VERSION 5.7 ;
  NOWIREEXTENSIONATPIN ON ;
  DIVIDERCHAR "/" ;
  BUSBITCHARS "[]" ;
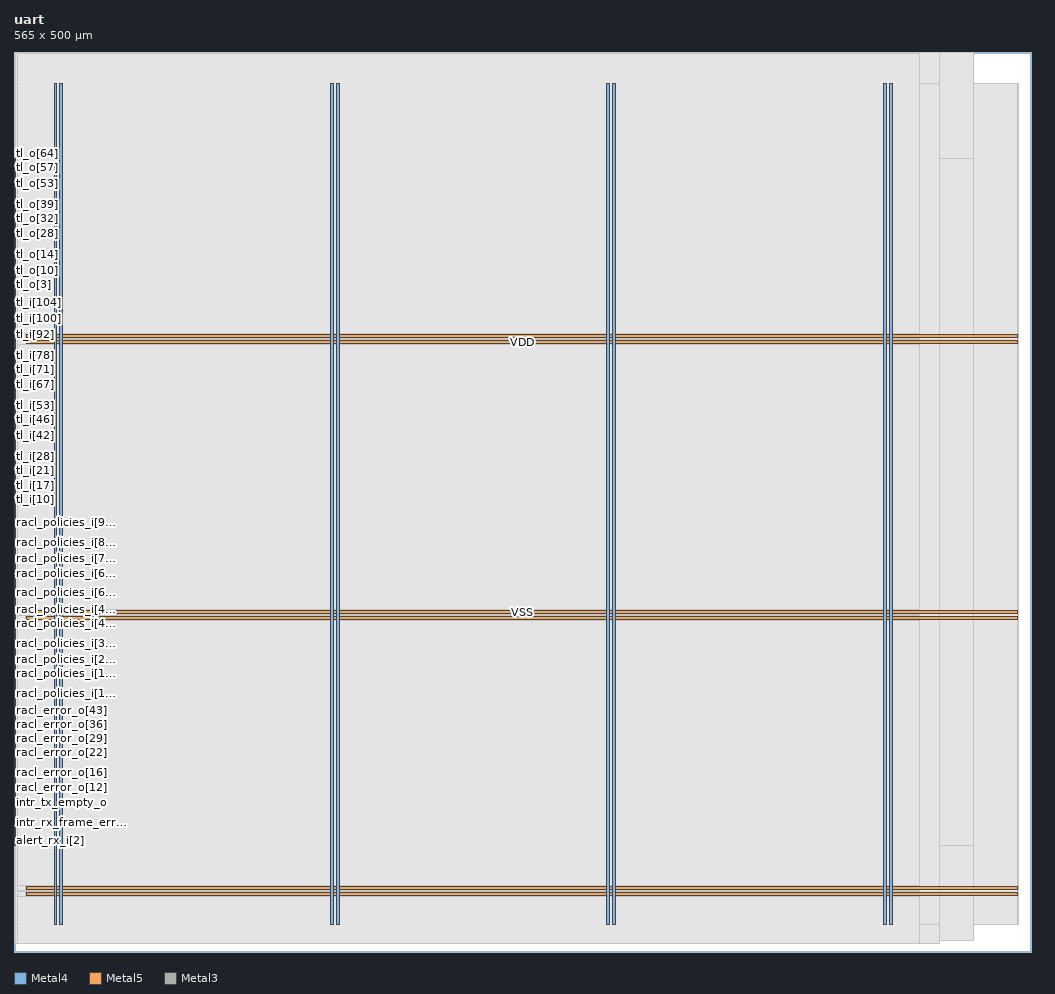
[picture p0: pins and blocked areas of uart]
MACRO uart
  CLASS BLOCK ;
  FOREIGN uart ;
  ORIGIN 0.000 0.000 ;
  SIZE 565.000 BY 500.000 ;
  PIN VDD
    DIRECTION INOUT ;
    USE POWER ;
    PORT
      LAYER Metal4 ;
        RECT 22.240 15.380 23.840 482.460 ;
    END
    PORT
      LAYER Metal4 ;
        RECT 175.840 15.380 177.440 482.460 ;
    END
    PORT
      LAYER Metal4 ;
        RECT 329.440 15.380 331.040 482.460 ;
    END
    PORT
      LAYER Metal4 ;
        RECT 483.040 15.380 484.640 482.460 ;
    END
    PORT
      LAYER Metal5 ;
        RECT 6.720 31.530 557.760 33.130 ;
    END
    PORT
      LAYER Metal5 ;
        RECT 6.720 184.710 557.760 186.310 ;
    END
    PORT
      LAYER Metal5 ;
        RECT 6.720 337.890 557.760 339.490 ;
    END
  END VDD
  PIN VSS
    DIRECTION INOUT ;
    USE GROUND ;
    PORT
      LAYER Metal4 ;
        RECT 25.540 15.380 27.140 482.460 ;
    END
    PORT
      LAYER Metal4 ;
        RECT 179.140 15.380 180.740 482.460 ;
    END
    PORT
      LAYER Metal4 ;
        RECT 332.740 15.380 334.340 482.460 ;
    END
    PORT
      LAYER Metal4 ;
        RECT 486.340 15.380 487.940 482.460 ;
    END
    PORT
      LAYER Metal5 ;
        RECT 6.720 34.830 557.760 36.430 ;
    END
    PORT
      LAYER Metal5 ;
        RECT 6.720 188.010 557.760 189.610 ;
    END
    PORT
      LAYER Metal5 ;
        RECT 6.720 341.190 557.760 342.790 ;
    END
  END VSS
  PIN alert_rx_i[0]
    DIRECTION INPUT ;
    USE SIGNAL ;
    ANTENNAGATEAREA 0.396000 ;
    PORT
      LAYER Metal3 ;
        RECT 0.000 59.360 0.560 59.920 ;
    END
  END alert_rx_i[0]
  PIN alert_rx_i[1]
    DIRECTION INPUT ;
    USE SIGNAL ;
    ANTENNAGATEAREA 0.396000 ;
    ANTENNADIFFAREA 0.410400 ;
    PORT
      LAYER Metal3 ;
        RECT 0.000 60.480 0.560 61.040 ;
    END
  END alert_rx_i[1]
  PIN alert_rx_i[2]
    DIRECTION INPUT ;
    USE SIGNAL ;
    ANTENNAGATEAREA 0.396000 ;
    ANTENNADIFFAREA 0.410400 ;
    PORT
      LAYER Metal3 ;
        RECT 0.000 61.600 0.560 62.160 ;
    END
  END alert_rx_i[2]
  PIN alert_rx_i[3]
    DIRECTION INPUT ;
    USE SIGNAL ;
    ANTENNAGATEAREA 0.396000 ;
    ANTENNADIFFAREA 0.410400 ;
    PORT
      LAYER Metal3 ;
        RECT 0.000 62.720 0.560 63.280 ;
    END
  END alert_rx_i[3]
  PIN alert_tx_o[0]
    DIRECTION OUTPUT ;
    USE SIGNAL ;
    ANTENNADIFFAREA 0.897600 ;
    PORT
      LAYER Metal3 ;
        RECT 0.000 63.840 0.560 64.400 ;
    END
  END alert_tx_o[0]
  PIN alert_tx_o[1]
    DIRECTION OUTPUT ;
    USE SIGNAL ;
    ANTENNADIFFAREA 0.897600 ;
    PORT
      LAYER Metal3 ;
        RECT 0.000 64.960 0.560 65.520 ;
    END
  END alert_tx_o[1]
  PIN cio_rx_i
    DIRECTION INPUT ;
    USE SIGNAL ;
    ANTENNAGATEAREA 0.396000 ;
    PORT
      LAYER Metal3 ;
        RECT 0.000 66.080 0.560 66.640 ;
    END
  END cio_rx_i
  PIN cio_tx_en_o
    DIRECTION OUTPUT ;
    USE SIGNAL ;
    ANTENNADIFFAREA 0.536800 ;
    PORT
      LAYER Metal3 ;
        RECT 0.000 67.200 0.560 67.760 ;
    END
  END cio_tx_en_o
  PIN cio_tx_o
    DIRECTION OUTPUT ;
    USE SIGNAL ;
    ANTENNADIFFAREA 0.897600 ;
    PORT
      LAYER Metal3 ;
        RECT 0.000 68.320 0.560 68.880 ;
    END
  END cio_tx_o
  PIN clk_i
    DIRECTION INPUT ;
    USE SIGNAL ;
    ANTENNAGATEAREA 4.738000 ;
    PORT
      LAYER Metal3 ;
        RECT 0.000 69.440 0.560 70.000 ;
    END
  END clk_i
  PIN intr_rx_break_err_o
    DIRECTION OUTPUT ;
    USE SIGNAL ;
    ANTENNADIFFAREA 0.897600 ;
    PORT
      LAYER Metal3 ;
        RECT 0.000 70.560 0.560 71.120 ;
    END
  END intr_rx_break_err_o
  PIN intr_rx_frame_err_o
    DIRECTION OUTPUT ;
    USE SIGNAL ;
    ANTENNADIFFAREA 0.897600 ;
    PORT
      LAYER Metal3 ;
        RECT 0.000 71.680 0.560 72.240 ;
    END
  END intr_rx_frame_err_o
  PIN intr_rx_overflow_o
    DIRECTION OUTPUT ;
    USE SIGNAL ;
    ANTENNADIFFAREA 0.897600 ;
    PORT
      LAYER Metal3 ;
        RECT 0.000 72.800 0.560 73.360 ;
    END
  END intr_rx_overflow_o
  PIN intr_rx_parity_err_o
    DIRECTION OUTPUT ;
    USE SIGNAL ;
    ANTENNADIFFAREA 0.897600 ;
    PORT
      LAYER Metal3 ;
        RECT 0.000 73.920 0.560 74.480 ;
    END
  END intr_rx_parity_err_o
  PIN intr_rx_timeout_o
    DIRECTION OUTPUT ;
    USE SIGNAL ;
    ANTENNADIFFAREA 0.897600 ;
    PORT
      LAYER Metal3 ;
        RECT 0.000 75.040 0.560 75.600 ;
    END
  END intr_rx_timeout_o
  PIN intr_rx_watermark_o
    DIRECTION OUTPUT ;
    USE SIGNAL ;
    ANTENNADIFFAREA 0.897600 ;
    PORT
      LAYER Metal3 ;
        RECT 0.000 76.160 0.560 76.720 ;
    END
  END intr_rx_watermark_o
  PIN intr_tx_done_o
    DIRECTION OUTPUT ;
    USE SIGNAL ;
    ANTENNADIFFAREA 0.897600 ;
    PORT
      LAYER Metal3 ;
        RECT 0.000 77.280 0.560 77.840 ;
    END
  END intr_tx_done_o
  PIN intr_tx_empty_o
    DIRECTION OUTPUT ;
    USE SIGNAL ;
    ANTENNADIFFAREA 0.897600 ;
    PORT
      LAYER Metal3 ;
        RECT 0.000 78.400 0.560 78.960 ;
    END
  END intr_tx_empty_o
  PIN intr_tx_watermark_o
    DIRECTION OUTPUT ;
    USE SIGNAL ;
    ANTENNADIFFAREA 0.897600 ;
    PORT
      LAYER Metal3 ;
        RECT 0.000 79.520 0.560 80.080 ;
    END
  END intr_tx_watermark_o
  PIN lsio_trigger_o
    DIRECTION OUTPUT ;
    USE SIGNAL ;
    ANTENNADIFFAREA 0.897600 ;
    PORT
      LAYER Metal3 ;
        RECT 0.000 80.640 0.560 81.200 ;
    END
  END lsio_trigger_o
  PIN racl_error_o[0]
    DIRECTION OUTPUT ;
    USE SIGNAL ;
    ANTENNADIFFAREA 0.360800 ;
    PORT
      LAYER Metal3 ;
        RECT 0.000 81.760 0.560 82.320 ;
    END
  END racl_error_o[0]
  PIN racl_error_o[10]
    DIRECTION OUTPUT ;
    USE SIGNAL ;
    ANTENNADIFFAREA 0.360800 ;
    PORT
      LAYER Metal3 ;
        RECT 0.000 92.960 0.560 93.520 ;
    END
  END racl_error_o[10]
  PIN racl_error_o[11]
    DIRECTION OUTPUT ;
    USE SIGNAL ;
    ANTENNADIFFAREA 0.360800 ;
    PORT
      LAYER Metal3 ;
        RECT 0.000 94.080 0.560 94.640 ;
    END
  END racl_error_o[11]
  PIN racl_error_o[12]
    DIRECTION OUTPUT ;
    USE SIGNAL ;
    ANTENNADIFFAREA 0.360800 ;
    PORT
      LAYER Metal3 ;
        RECT 0.000 95.200 0.560 95.760 ;
    END
  END racl_error_o[12]
  PIN racl_error_o[13]
    DIRECTION OUTPUT ;
    USE SIGNAL ;
    ANTENNADIFFAREA 0.360800 ;
    PORT
      LAYER Metal3 ;
        RECT 0.000 96.320 0.560 96.880 ;
    END
  END racl_error_o[13]
  PIN racl_error_o[14]
    DIRECTION OUTPUT ;
    USE SIGNAL ;
    ANTENNADIFFAREA 0.360800 ;
    PORT
      LAYER Metal3 ;
        RECT 0.000 97.440 0.560 98.000 ;
    END
  END racl_error_o[14]
  PIN racl_error_o[15]
    DIRECTION OUTPUT ;
    USE SIGNAL ;
    ANTENNADIFFAREA 0.360800 ;
    PORT
      LAYER Metal3 ;
        RECT 0.000 98.560 0.560 99.120 ;
    END
  END racl_error_o[15]
  PIN racl_error_o[16]
    DIRECTION OUTPUT ;
    USE SIGNAL ;
    ANTENNADIFFAREA 0.360800 ;
    PORT
      LAYER Metal3 ;
        RECT 0.000 99.680 0.560 100.240 ;
    END
  END racl_error_o[16]
  PIN racl_error_o[17]
    DIRECTION OUTPUT ;
    USE SIGNAL ;
    ANTENNADIFFAREA 0.360800 ;
    PORT
      LAYER Metal3 ;
        RECT 0.000 100.800 0.560 101.360 ;
    END
  END racl_error_o[17]
  PIN racl_error_o[18]
    DIRECTION OUTPUT ;
    USE SIGNAL ;
    ANTENNADIFFAREA 0.360800 ;
    PORT
      LAYER Metal3 ;
        RECT 0.000 101.920 0.560 102.480 ;
    END
  END racl_error_o[18]
  PIN racl_error_o[19]
    DIRECTION OUTPUT ;
    USE SIGNAL ;
    ANTENNADIFFAREA 0.360800 ;
    PORT
      LAYER Metal3 ;
        RECT 0.000 103.040 0.560 103.600 ;
    END
  END racl_error_o[19]
  PIN racl_error_o[1]
    DIRECTION OUTPUT ;
    USE SIGNAL ;
    ANTENNADIFFAREA 0.360800 ;
    PORT
      LAYER Metal3 ;
        RECT 0.000 82.880 0.560 83.440 ;
    END
  END racl_error_o[1]
  PIN racl_error_o[20]
    DIRECTION OUTPUT ;
    USE SIGNAL ;
    ANTENNADIFFAREA 0.360800 ;
    PORT
      LAYER Metal3 ;
        RECT 0.000 104.160 0.560 104.720 ;
    END
  END racl_error_o[20]
  PIN racl_error_o[21]
    DIRECTION OUTPUT ;
    USE SIGNAL ;
    ANTENNADIFFAREA 0.360800 ;
    PORT
      LAYER Metal3 ;
        RECT 0.000 105.280 0.560 105.840 ;
    END
  END racl_error_o[21]
  PIN racl_error_o[22]
    DIRECTION OUTPUT ;
    USE SIGNAL ;
    ANTENNADIFFAREA 0.360800 ;
    PORT
      LAYER Metal3 ;
        RECT 0.000 106.400 0.560 106.960 ;
    END
  END racl_error_o[22]
  PIN racl_error_o[23]
    DIRECTION OUTPUT ;
    USE SIGNAL ;
    ANTENNADIFFAREA 0.360800 ;
    PORT
      LAYER Metal3 ;
        RECT 0.000 107.520 0.560 108.080 ;
    END
  END racl_error_o[23]
  PIN racl_error_o[24]
    DIRECTION OUTPUT ;
    USE SIGNAL ;
    ANTENNADIFFAREA 0.360800 ;
    PORT
      LAYER Metal3 ;
        RECT 0.000 108.640 0.560 109.200 ;
    END
  END racl_error_o[24]
  PIN racl_error_o[25]
    DIRECTION OUTPUT ;
    USE SIGNAL ;
    ANTENNADIFFAREA 0.360800 ;
    PORT
      LAYER Metal3 ;
        RECT 0.000 109.760 0.560 110.320 ;
    END
  END racl_error_o[25]
  PIN racl_error_o[26]
    DIRECTION OUTPUT ;
    USE SIGNAL ;
    ANTENNADIFFAREA 0.360800 ;
    PORT
      LAYER Metal3 ;
        RECT 0.000 110.880 0.560 111.440 ;
    END
  END racl_error_o[26]
  PIN racl_error_o[27]
    DIRECTION OUTPUT ;
    USE SIGNAL ;
    ANTENNADIFFAREA 0.360800 ;
    PORT
      LAYER Metal3 ;
        RECT 0.000 112.000 0.560 112.560 ;
    END
  END racl_error_o[27]
  PIN racl_error_o[28]
    DIRECTION OUTPUT ;
    USE SIGNAL ;
    ANTENNADIFFAREA 0.360800 ;
    PORT
      LAYER Metal3 ;
        RECT 0.000 113.120 0.560 113.680 ;
    END
  END racl_error_o[28]
  PIN racl_error_o[29]
    DIRECTION OUTPUT ;
    USE SIGNAL ;
    ANTENNADIFFAREA 0.360800 ;
    PORT
      LAYER Metal3 ;
        RECT 0.000 114.240 0.560 114.800 ;
    END
  END racl_error_o[29]
  PIN racl_error_o[2]
    DIRECTION OUTPUT ;
    USE SIGNAL ;
    ANTENNADIFFAREA 0.897600 ;
    PORT
      LAYER Metal3 ;
        RECT 0.000 84.000 0.560 84.560 ;
    END
  END racl_error_o[2]
  PIN racl_error_o[30]
    DIRECTION OUTPUT ;
    USE SIGNAL ;
    ANTENNADIFFAREA 0.360800 ;
    PORT
      LAYER Metal3 ;
        RECT 0.000 115.360 0.560 115.920 ;
    END
  END racl_error_o[30]
  PIN racl_error_o[31]
    DIRECTION OUTPUT ;
    USE SIGNAL ;
    ANTENNADIFFAREA 0.360800 ;
    PORT
      LAYER Metal3 ;
        RECT 0.000 116.480 0.560 117.040 ;
    END
  END racl_error_o[31]
  PIN racl_error_o[32]
    DIRECTION OUTPUT ;
    USE SIGNAL ;
    ANTENNADIFFAREA 0.360800 ;
    PORT
      LAYER Metal3 ;
        RECT 0.000 117.600 0.560 118.160 ;
    END
  END racl_error_o[32]
  PIN racl_error_o[33]
    DIRECTION OUTPUT ;
    USE SIGNAL ;
    ANTENNADIFFAREA 0.360800 ;
    PORT
      LAYER Metal3 ;
        RECT 0.000 118.720 0.560 119.280 ;
    END
  END racl_error_o[33]
  PIN racl_error_o[34]
    DIRECTION OUTPUT ;
    USE SIGNAL ;
    ANTENNADIFFAREA 0.360800 ;
    PORT
      LAYER Metal3 ;
        RECT 0.000 119.840 0.560 120.400 ;
    END
  END racl_error_o[34]
  PIN racl_error_o[35]
    DIRECTION OUTPUT ;
    USE SIGNAL ;
    ANTENNADIFFAREA 0.360800 ;
    PORT
      LAYER Metal3 ;
        RECT 0.000 120.960 0.560 121.520 ;
    END
  END racl_error_o[35]
  PIN racl_error_o[36]
    DIRECTION OUTPUT ;
    USE SIGNAL ;
    ANTENNADIFFAREA 0.360800 ;
    PORT
      LAYER Metal3 ;
        RECT 0.000 122.080 0.560 122.640 ;
    END
  END racl_error_o[36]
  PIN racl_error_o[37]
    DIRECTION OUTPUT ;
    USE SIGNAL ;
    ANTENNADIFFAREA 0.360800 ;
    PORT
      LAYER Metal3 ;
        RECT 0.000 123.200 0.560 123.760 ;
    END
  END racl_error_o[37]
  PIN racl_error_o[38]
    DIRECTION OUTPUT ;
    USE SIGNAL ;
    ANTENNADIFFAREA 0.360800 ;
    PORT
      LAYER Metal3 ;
        RECT 0.000 124.320 0.560 124.880 ;
    END
  END racl_error_o[38]
  PIN racl_error_o[39]
    DIRECTION OUTPUT ;
    USE SIGNAL ;
    ANTENNADIFFAREA 0.360800 ;
    PORT
      LAYER Metal3 ;
        RECT 0.000 125.440 0.560 126.000 ;
    END
  END racl_error_o[39]
  PIN racl_error_o[3]
    DIRECTION OUTPUT ;
    USE SIGNAL ;
    ANTENNADIFFAREA 0.897600 ;
    PORT
      LAYER Metal3 ;
        RECT 0.000 85.120 0.560 85.680 ;
    END
  END racl_error_o[3]
  PIN racl_error_o[40]
    DIRECTION OUTPUT ;
    USE SIGNAL ;
    ANTENNADIFFAREA 0.360800 ;
    PORT
      LAYER Metal3 ;
        RECT 0.000 126.560 0.560 127.120 ;
    END
  END racl_error_o[40]
  PIN racl_error_o[41]
    DIRECTION OUTPUT ;
    USE SIGNAL ;
    ANTENNADIFFAREA 0.360800 ;
    PORT
      LAYER Metal3 ;
        RECT 0.000 127.680 0.560 128.240 ;
    END
  END racl_error_o[41]
  PIN racl_error_o[42]
    DIRECTION OUTPUT ;
    USE SIGNAL ;
    ANTENNADIFFAREA 0.360800 ;
    PORT
      LAYER Metal3 ;
        RECT 0.000 128.800 0.560 129.360 ;
    END
  END racl_error_o[42]
  PIN racl_error_o[43]
    DIRECTION OUTPUT ;
    USE SIGNAL ;
    ANTENNADIFFAREA 0.360800 ;
    PORT
      LAYER Metal3 ;
        RECT 0.000 129.920 0.560 130.480 ;
    END
  END racl_error_o[43]
  PIN racl_error_o[4]
    DIRECTION OUTPUT ;
    USE SIGNAL ;
    ANTENNADIFFAREA 0.897600 ;
    PORT
      LAYER Metal3 ;
        RECT 0.000 86.240 0.560 86.800 ;
    END
  END racl_error_o[4]
  PIN racl_error_o[5]
    DIRECTION OUTPUT ;
    USE SIGNAL ;
    ANTENNADIFFAREA 0.897600 ;
    PORT
      LAYER Metal3 ;
        RECT 0.000 87.360 0.560 87.920 ;
    END
  END racl_error_o[5]
  PIN racl_error_o[6]
    DIRECTION OUTPUT ;
    USE SIGNAL ;
    ANTENNADIFFAREA 0.360800 ;
    PORT
      LAYER Metal3 ;
        RECT 0.000 88.480 0.560 89.040 ;
    END
  END racl_error_o[6]
  PIN racl_error_o[7]
    DIRECTION OUTPUT ;
    USE SIGNAL ;
    ANTENNADIFFAREA 0.360800 ;
    PORT
      LAYER Metal3 ;
        RECT 0.000 89.600 0.560 90.160 ;
    END
  END racl_error_o[7]
  PIN racl_error_o[8]
    DIRECTION OUTPUT ;
    USE SIGNAL ;
    ANTENNADIFFAREA 0.360800 ;
    PORT
      LAYER Metal3 ;
        RECT 0.000 90.720 0.560 91.280 ;
    END
  END racl_error_o[8]
  PIN racl_error_o[9]
    DIRECTION OUTPUT ;
    USE SIGNAL ;
    ANTENNADIFFAREA 0.360800 ;
    PORT
      LAYER Metal3 ;
        RECT 0.000 91.840 0.560 92.400 ;
    END
  END racl_error_o[9]
  PIN racl_policies_i[0]
    DIRECTION INPUT ;
    USE SIGNAL ;
    PORT
      LAYER Metal3 ;
        RECT 0.000 131.040 0.560 131.600 ;
    END
  END racl_policies_i[0]
  PIN racl_policies_i[10]
    DIRECTION INPUT ;
    USE SIGNAL ;
    PORT
      LAYER Metal3 ;
        RECT 0.000 142.240 0.560 142.800 ;
    END
  END racl_policies_i[10]
  PIN racl_policies_i[11]
    DIRECTION INPUT ;
    USE SIGNAL ;
    PORT
      LAYER Metal3 ;
        RECT 0.000 143.360 0.560 143.920 ;
    END
  END racl_policies_i[11]
  PIN racl_policies_i[12]
    DIRECTION INPUT ;
    USE SIGNAL ;
    PORT
      LAYER Metal3 ;
        RECT 0.000 144.480 0.560 145.040 ;
    END
  END racl_policies_i[12]
  PIN racl_policies_i[13]
    DIRECTION INPUT ;
    USE SIGNAL ;
    PORT
      LAYER Metal3 ;
        RECT 0.000 145.600 0.560 146.160 ;
    END
  END racl_policies_i[13]
  PIN racl_policies_i[14]
    DIRECTION INPUT ;
    USE SIGNAL ;
    PORT
      LAYER Metal3 ;
        RECT 0.000 146.720 0.560 147.280 ;
    END
  END racl_policies_i[14]
  PIN racl_policies_i[15]
    DIRECTION INPUT ;
    USE SIGNAL ;
    PORT
      LAYER Metal3 ;
        RECT 0.000 147.840 0.560 148.400 ;
    END
  END racl_policies_i[15]
  PIN racl_policies_i[16]
    DIRECTION INPUT ;
    USE SIGNAL ;
    PORT
      LAYER Metal3 ;
        RECT 0.000 148.960 0.560 149.520 ;
    END
  END racl_policies_i[16]
  PIN racl_policies_i[17]
    DIRECTION INPUT ;
    USE SIGNAL ;
    PORT
      LAYER Metal3 ;
        RECT 0.000 150.080 0.560 150.640 ;
    END
  END racl_policies_i[17]
  PIN racl_policies_i[18]
    DIRECTION INPUT ;
    USE SIGNAL ;
    PORT
      LAYER Metal3 ;
        RECT 0.000 151.200 0.560 151.760 ;
    END
  END racl_policies_i[18]
  PIN racl_policies_i[19]
    DIRECTION INPUT ;
    USE SIGNAL ;
    PORT
      LAYER Metal3 ;
        RECT 0.000 152.320 0.560 152.880 ;
    END
  END racl_policies_i[19]
  PIN racl_policies_i[1]
    DIRECTION INPUT ;
    USE SIGNAL ;
    PORT
      LAYER Metal3 ;
        RECT 0.000 132.160 0.560 132.720 ;
    END
  END racl_policies_i[1]
  PIN racl_policies_i[20]
    DIRECTION INPUT ;
    USE SIGNAL ;
    PORT
      LAYER Metal3 ;
        RECT 0.000 153.440 0.560 154.000 ;
    END
  END racl_policies_i[20]
  PIN racl_policies_i[21]
    DIRECTION INPUT ;
    USE SIGNAL ;
    PORT
      LAYER Metal3 ;
        RECT 0.000 154.560 0.560 155.120 ;
    END
  END racl_policies_i[21]
  PIN racl_policies_i[22]
    DIRECTION INPUT ;
    USE SIGNAL ;
    PORT
      LAYER Metal3 ;
        RECT 0.000 155.680 0.560 156.240 ;
    END
  END racl_policies_i[22]
  PIN racl_policies_i[23]
    DIRECTION INPUT ;
    USE SIGNAL ;
    PORT
      LAYER Metal3 ;
        RECT 0.000 156.800 0.560 157.360 ;
    END
  END racl_policies_i[23]
  PIN racl_policies_i[24]
    DIRECTION INPUT ;
    USE SIGNAL ;
    PORT
      LAYER Metal3 ;
        RECT 0.000 157.920 0.560 158.480 ;
    END
  END racl_policies_i[24]
  PIN racl_policies_i[25]
    DIRECTION INPUT ;
    USE SIGNAL ;
    PORT
      LAYER Metal3 ;
        RECT 0.000 159.040 0.560 159.600 ;
    END
  END racl_policies_i[25]
  PIN racl_policies_i[26]
    DIRECTION INPUT ;
    USE SIGNAL ;
    PORT
      LAYER Metal3 ;
        RECT 0.000 160.160 0.560 160.720 ;
    END
  END racl_policies_i[26]
  PIN racl_policies_i[27]
    DIRECTION INPUT ;
    USE SIGNAL ;
    PORT
      LAYER Metal3 ;
        RECT 0.000 161.280 0.560 161.840 ;
    END
  END racl_policies_i[27]
  PIN racl_policies_i[28]
    DIRECTION INPUT ;
    USE SIGNAL ;
    PORT
      LAYER Metal3 ;
        RECT 0.000 162.400 0.560 162.960 ;
    END
  END racl_policies_i[28]
  PIN racl_policies_i[29]
    DIRECTION INPUT ;
    USE SIGNAL ;
    PORT
      LAYER Metal3 ;
        RECT 0.000 163.520 0.560 164.080 ;
    END
  END racl_policies_i[29]
  PIN racl_policies_i[2]
    DIRECTION INPUT ;
    USE SIGNAL ;
    PORT
      LAYER Metal3 ;
        RECT 0.000 133.280 0.560 133.840 ;
    END
  END racl_policies_i[2]
  PIN racl_policies_i[30]
    DIRECTION INPUT ;
    USE SIGNAL ;
    PORT
      LAYER Metal3 ;
        RECT 0.000 164.640 0.560 165.200 ;
    END
  END racl_policies_i[30]
  PIN racl_policies_i[31]
    DIRECTION INPUT ;
    USE SIGNAL ;
    PORT
      LAYER Metal3 ;
        RECT 0.000 165.760 0.560 166.320 ;
    END
  END racl_policies_i[31]
  PIN racl_policies_i[32]
    DIRECTION INPUT ;
    USE SIGNAL ;
    PORT
      LAYER Metal3 ;
        RECT 0.000 166.880 0.560 167.440 ;
    END
  END racl_policies_i[32]
  PIN racl_policies_i[33]
    DIRECTION INPUT ;
    USE SIGNAL ;
    PORT
      LAYER Metal3 ;
        RECT 0.000 168.000 0.560 168.560 ;
    END
  END racl_policies_i[33]
  PIN racl_policies_i[34]
    DIRECTION INPUT ;
    USE SIGNAL ;
    PORT
      LAYER Metal3 ;
        RECT 0.000 169.120 0.560 169.680 ;
    END
  END racl_policies_i[34]
  PIN racl_policies_i[35]
    DIRECTION INPUT ;
    USE SIGNAL ;
    PORT
      LAYER Metal3 ;
        RECT 0.000 170.240 0.560 170.800 ;
    END
  END racl_policies_i[35]
  PIN racl_policies_i[36]
    DIRECTION INPUT ;
    USE SIGNAL ;
    PORT
      LAYER Metal3 ;
        RECT 0.000 171.360 0.560 171.920 ;
    END
  END racl_policies_i[36]
  PIN racl_policies_i[37]
    DIRECTION INPUT ;
    USE SIGNAL ;
    PORT
      LAYER Metal3 ;
        RECT 0.000 172.480 0.560 173.040 ;
    END
  END racl_policies_i[37]
  PIN racl_policies_i[38]
    DIRECTION INPUT ;
    USE SIGNAL ;
    PORT
      LAYER Metal3 ;
        RECT 0.000 173.600 0.560 174.160 ;
    END
  END racl_policies_i[38]
  PIN racl_policies_i[39]
    DIRECTION INPUT ;
    USE SIGNAL ;
    PORT
      LAYER Metal3 ;
        RECT 0.000 174.720 0.560 175.280 ;
    END
  END racl_policies_i[39]
  PIN racl_policies_i[3]
    DIRECTION INPUT ;
    USE SIGNAL ;
    PORT
      LAYER Metal3 ;
        RECT 0.000 134.400 0.560 134.960 ;
    END
  END racl_policies_i[3]
  PIN racl_policies_i[40]
    DIRECTION INPUT ;
    USE SIGNAL ;
    PORT
      LAYER Metal3 ;
        RECT 0.000 175.840 0.560 176.400 ;
    END
  END racl_policies_i[40]
  PIN racl_policies_i[41]
    DIRECTION INPUT ;
    USE SIGNAL ;
    PORT
      LAYER Metal3 ;
        RECT 0.000 176.960 0.560 177.520 ;
    END
  END racl_policies_i[41]
  PIN racl_policies_i[42]
    DIRECTION INPUT ;
    USE SIGNAL ;
    PORT
      LAYER Metal3 ;
        RECT 0.000 178.080 0.560 178.640 ;
    END
  END racl_policies_i[42]
  PIN racl_policies_i[43]
    DIRECTION INPUT ;
    USE SIGNAL ;
    PORT
      LAYER Metal3 ;
        RECT 0.000 179.200 0.560 179.760 ;
    END
  END racl_policies_i[43]
  PIN racl_policies_i[44]
    DIRECTION INPUT ;
    USE SIGNAL ;
    PORT
      LAYER Metal3 ;
        RECT 0.000 180.320 0.560 180.880 ;
    END
  END racl_policies_i[44]
  PIN racl_policies_i[45]
    DIRECTION INPUT ;
    USE SIGNAL ;
    PORT
      LAYER Metal3 ;
        RECT 0.000 181.440 0.560 182.000 ;
    END
  END racl_policies_i[45]
  PIN racl_policies_i[46]
    DIRECTION INPUT ;
    USE SIGNAL ;
    PORT
      LAYER Metal3 ;
        RECT 0.000 182.560 0.560 183.120 ;
    END
  END racl_policies_i[46]
  PIN racl_policies_i[47]
    DIRECTION INPUT ;
    USE SIGNAL ;
    PORT
      LAYER Metal3 ;
        RECT 0.000 183.680 0.560 184.240 ;
    END
  END racl_policies_i[47]
  PIN racl_policies_i[48]
    DIRECTION INPUT ;
    USE SIGNAL ;
    PORT
      LAYER Metal3 ;
        RECT 0.000 184.800 0.560 185.360 ;
    END
  END racl_policies_i[48]
  PIN racl_policies_i[49]
    DIRECTION INPUT ;
    USE SIGNAL ;
    PORT
      LAYER Metal3 ;
        RECT 0.000 185.920 0.560 186.480 ;
    END
  END racl_policies_i[49]
  PIN racl_policies_i[4]
    DIRECTION INPUT ;
    USE SIGNAL ;
    PORT
      LAYER Metal3 ;
        RECT 0.000 135.520 0.560 136.080 ;
    END
  END racl_policies_i[4]
  PIN racl_policies_i[50]
    DIRECTION INPUT ;
    USE SIGNAL ;
    PORT
      LAYER Metal3 ;
        RECT 0.000 187.040 0.560 187.600 ;
    END
  END racl_policies_i[50]
  PIN racl_policies_i[51]
    DIRECTION INPUT ;
    USE SIGNAL ;
    PORT
      LAYER Metal3 ;
        RECT 0.000 188.160 0.560 188.720 ;
    END
  END racl_policies_i[51]
  PIN racl_policies_i[52]
    DIRECTION INPUT ;
    USE SIGNAL ;
    PORT
      LAYER Metal3 ;
        RECT 0.000 189.280 0.560 189.840 ;
    END
  END racl_policies_i[52]
  PIN racl_policies_i[53]
    DIRECTION INPUT ;
    USE SIGNAL ;
    PORT
      LAYER Metal3 ;
        RECT 0.000 190.400 0.560 190.960 ;
    END
  END racl_policies_i[53]
  PIN racl_policies_i[54]
    DIRECTION INPUT ;
    USE SIGNAL ;
    PORT
      LAYER Metal3 ;
        RECT 0.000 191.520 0.560 192.080 ;
    END
  END racl_policies_i[54]
  PIN racl_policies_i[55]
    DIRECTION INPUT ;
    USE SIGNAL ;
    PORT
      LAYER Metal3 ;
        RECT 0.000 192.640 0.560 193.200 ;
    END
  END racl_policies_i[55]
  PIN racl_policies_i[56]
    DIRECTION INPUT ;
    USE SIGNAL ;
    PORT
      LAYER Metal3 ;
        RECT 0.000 193.760 0.560 194.320 ;
    END
  END racl_policies_i[56]
  PIN racl_policies_i[57]
    DIRECTION INPUT ;
    USE SIGNAL ;
    PORT
      LAYER Metal3 ;
        RECT 0.000 194.880 0.560 195.440 ;
    END
  END racl_policies_i[57]
  PIN racl_policies_i[58]
    DIRECTION INPUT ;
    USE SIGNAL ;
    PORT
      LAYER Metal3 ;
        RECT 0.000 196.000 0.560 196.560 ;
    END
  END racl_policies_i[58]
  PIN racl_policies_i[59]
    DIRECTION INPUT ;
    USE SIGNAL ;
    PORT
      LAYER Metal3 ;
        RECT 0.000 197.120 0.560 197.680 ;
    END
  END racl_policies_i[59]
  PIN racl_policies_i[5]
    DIRECTION INPUT ;
    USE SIGNAL ;
    PORT
      LAYER Metal3 ;
        RECT 0.000 136.640 0.560 137.200 ;
    END
  END racl_policies_i[5]
  PIN racl_policies_i[60]
    DIRECTION INPUT ;
    USE SIGNAL ;
    PORT
      LAYER Metal3 ;
        RECT 0.000 198.240 0.560 198.800 ;
    END
  END racl_policies_i[60]
  PIN racl_policies_i[61]
    DIRECTION INPUT ;
    USE SIGNAL ;
    PORT
      LAYER Metal3 ;
        RECT 0.000 199.360 0.560 199.920 ;
    END
  END racl_policies_i[61]
  PIN racl_policies_i[62]
    DIRECTION INPUT ;
    USE SIGNAL ;
    PORT
      LAYER Metal3 ;
        RECT 0.000 200.480 0.560 201.040 ;
    END
  END racl_policies_i[62]
  PIN racl_policies_i[63]
    DIRECTION INPUT ;
    USE SIGNAL ;
    PORT
      LAYER Metal3 ;
        RECT 0.000 201.600 0.560 202.160 ;
    END
  END racl_policies_i[63]
  PIN racl_policies_i[64]
    DIRECTION INPUT ;
    USE SIGNAL ;
    PORT
      LAYER Metal3 ;
        RECT 0.000 202.720 0.560 203.280 ;
    END
  END racl_policies_i[64]
  PIN racl_policies_i[65]
    DIRECTION INPUT ;
    USE SIGNAL ;
    PORT
      LAYER Metal3 ;
        RECT 0.000 203.840 0.560 204.400 ;
    END
  END racl_policies_i[65]
  PIN racl_policies_i[66]
    DIRECTION INPUT ;
    USE SIGNAL ;
    PORT
      LAYER Metal3 ;
        RECT 0.000 204.960 0.560 205.520 ;
    END
  END racl_policies_i[66]
  PIN racl_policies_i[67]
    DIRECTION INPUT ;
    USE SIGNAL ;
    PORT
      LAYER Metal3 ;
        RECT 0.000 206.080 0.560 206.640 ;
    END
  END racl_policies_i[67]
  PIN racl_policies_i[68]
    DIRECTION INPUT ;
    USE SIGNAL ;
    PORT
      LAYER Metal3 ;
        RECT 0.000 207.200 0.560 207.760 ;
    END
  END racl_policies_i[68]
  PIN racl_policies_i[69]
    DIRECTION INPUT ;
    USE SIGNAL ;
    PORT
      LAYER Metal3 ;
        RECT 0.000 208.320 0.560 208.880 ;
    END
  END racl_policies_i[69]
  PIN racl_policies_i[6]
    DIRECTION INPUT ;
    USE SIGNAL ;
    PORT
      LAYER Metal3 ;
        RECT 0.000 137.760 0.560 138.320 ;
    END
  END racl_policies_i[6]
  PIN racl_policies_i[70]
    DIRECTION INPUT ;
    USE SIGNAL ;
    PORT
      LAYER Metal3 ;
        RECT 0.000 209.440 0.560 210.000 ;
    END
  END racl_policies_i[70]
  PIN racl_policies_i[71]
    DIRECTION INPUT ;
    USE SIGNAL ;
    PORT
      LAYER Metal3 ;
        RECT 0.000 210.560 0.560 211.120 ;
    END
  END racl_policies_i[71]
  PIN racl_policies_i[72]
    DIRECTION INPUT ;
    USE SIGNAL ;
    PORT
      LAYER Metal3 ;
        RECT 0.000 211.680 0.560 212.240 ;
    END
  END racl_policies_i[72]
  PIN racl_policies_i[73]
    DIRECTION INPUT ;
    USE SIGNAL ;
    PORT
      LAYER Metal3 ;
        RECT 0.000 212.800 0.560 213.360 ;
    END
  END racl_policies_i[73]
  PIN racl_policies_i[74]
    DIRECTION INPUT ;
    USE SIGNAL ;
    PORT
      LAYER Metal3 ;
        RECT 0.000 213.920 0.560 214.480 ;
    END
  END racl_policies_i[74]
  PIN racl_policies_i[75]
    DIRECTION INPUT ;
    USE SIGNAL ;
    PORT
      LAYER Metal3 ;
        RECT 0.000 215.040 0.560 215.600 ;
    END
  END racl_policies_i[75]
  PIN racl_policies_i[76]
    DIRECTION INPUT ;
    USE SIGNAL ;
    PORT
      LAYER Metal3 ;
        RECT 0.000 216.160 0.560 216.720 ;
    END
  END racl_policies_i[76]
  PIN racl_policies_i[77]
    DIRECTION INPUT ;
    USE SIGNAL ;
    PORT
      LAYER Metal3 ;
        RECT 0.000 217.280 0.560 217.840 ;
    END
  END racl_policies_i[77]
  PIN racl_policies_i[78]
    DIRECTION INPUT ;
    USE SIGNAL ;
    PORT
      LAYER Metal3 ;
        RECT 0.000 218.400 0.560 218.960 ;
    END
  END racl_policies_i[78]
  PIN racl_policies_i[79]
    DIRECTION INPUT ;
    USE SIGNAL ;
    PORT
      LAYER Metal3 ;
        RECT 0.000 219.520 0.560 220.080 ;
    END
  END racl_policies_i[79]
  PIN racl_policies_i[7]
    DIRECTION INPUT ;
    USE SIGNAL ;
    PORT
      LAYER Metal3 ;
        RECT 0.000 138.880 0.560 139.440 ;
    END
  END racl_policies_i[7]
  PIN racl_policies_i[80]
    DIRECTION INPUT ;
    USE SIGNAL ;
    PORT
      LAYER Metal3 ;
        RECT 0.000 220.640 0.560 221.200 ;
    END
  END racl_policies_i[80]
  PIN racl_policies_i[81]
    DIRECTION INPUT ;
    USE SIGNAL ;
    PORT
      LAYER Metal3 ;
        RECT 0.000 221.760 0.560 222.320 ;
    END
  END racl_policies_i[81]
  PIN racl_policies_i[82]
    DIRECTION INPUT ;
    USE SIGNAL ;
    PORT
      LAYER Metal3 ;
        RECT 0.000 222.880 0.560 223.440 ;
    END
  END racl_policies_i[82]
  PIN racl_policies_i[83]
    DIRECTION INPUT ;
    USE SIGNAL ;
    PORT
      LAYER Metal3 ;
        RECT 0.000 224.000 0.560 224.560 ;
    END
  END racl_policies_i[83]
  PIN racl_policies_i[84]
    DIRECTION INPUT ;
    USE SIGNAL ;
    PORT
      LAYER Metal3 ;
        RECT 0.000 225.120 0.560 225.680 ;
    END
  END racl_policies_i[84]
  PIN racl_policies_i[85]
    DIRECTION INPUT ;
    USE SIGNAL ;
    PORT
      LAYER Metal3 ;
        RECT 0.000 226.240 0.560 226.800 ;
    END
  END racl_policies_i[85]
  PIN racl_policies_i[86]
    DIRECTION INPUT ;
    USE SIGNAL ;
    PORT
      LAYER Metal3 ;
        RECT 0.000 227.360 0.560 227.920 ;
    END
  END racl_policies_i[86]
  PIN racl_policies_i[87]
    DIRECTION INPUT ;
    USE SIGNAL ;
    PORT
      LAYER Metal3 ;
        RECT 0.000 228.480 0.560 229.040 ;
    END
  END racl_policies_i[87]
  PIN racl_policies_i[88]
    DIRECTION INPUT ;
    USE SIGNAL ;
    PORT
      LAYER Metal3 ;
        RECT 0.000 229.600 0.560 230.160 ;
    END
  END racl_policies_i[88]
  PIN racl_policies_i[89]
    DIRECTION INPUT ;
    USE SIGNAL ;
    PORT
      LAYER Metal3 ;
        RECT 0.000 230.720 0.560 231.280 ;
    END
  END racl_policies_i[89]
  PIN racl_policies_i[8]
    DIRECTION INPUT ;
    USE SIGNAL ;
    PORT
      LAYER Metal3 ;
        RECT 0.000 140.000 0.560 140.560 ;
    END
  END racl_policies_i[8]
  PIN racl_policies_i[90]
    DIRECTION INPUT ;
    USE SIGNAL ;
    PORT
      LAYER Metal3 ;
        RECT 0.000 231.840 0.560 232.400 ;
    END
  END racl_policies_i[90]
  PIN racl_policies_i[91]
    DIRECTION INPUT ;
    USE SIGNAL ;
    PORT
      LAYER Metal3 ;
        RECT 0.000 232.960 0.560 233.520 ;
    END
  END racl_policies_i[91]
  PIN racl_policies_i[92]
    DIRECTION INPUT ;
    USE SIGNAL ;
    PORT
      LAYER Metal3 ;
        RECT 0.000 234.080 0.560 234.640 ;
    END
  END racl_policies_i[92]
  PIN racl_policies_i[93]
    DIRECTION INPUT ;
    USE SIGNAL ;
    PORT
      LAYER Metal3 ;
        RECT 0.000 235.200 0.560 235.760 ;
    END
  END racl_policies_i[93]
  PIN racl_policies_i[94]
    DIRECTION INPUT ;
    USE SIGNAL ;
    PORT
      LAYER Metal3 ;
        RECT 0.000 236.320 0.560 236.880 ;
    END
  END racl_policies_i[94]
  PIN racl_policies_i[95]
    DIRECTION INPUT ;
    USE SIGNAL ;
    PORT
      LAYER Metal3 ;
        RECT 0.000 237.440 0.560 238.000 ;
    END
  END racl_policies_i[95]
  PIN racl_policies_i[9]
    DIRECTION INPUT ;
    USE SIGNAL ;
    PORT
      LAYER Metal3 ;
        RECT 0.000 141.120 0.560 141.680 ;
    END
  END racl_policies_i[9]
  PIN rst_ni
    DIRECTION INPUT ;
    USE SIGNAL ;
    ANTENNAGATEAREA 0.396000 ;
    PORT
      LAYER Metal3 ;
        RECT 0.000 238.560 0.560 239.120 ;
    END
  END rst_ni
  PIN tl_i[0]
    DIRECTION INPUT ;
    USE SIGNAL ;
    ANTENNAGATEAREA 0.396000 ;
    PORT
      LAYER Metal3 ;
        RECT 0.000 239.680 0.560 240.240 ;
    END
  END tl_i[0]
  PIN tl_i[100]
    DIRECTION INPUT ;
    USE SIGNAL ;
    ANTENNAGATEAREA 0.396000 ;
    PORT
      LAYER Metal3 ;
        RECT 0.000 351.680 0.560 352.240 ;
    END
  END tl_i[100]
  PIN tl_i[101]
    DIRECTION INPUT ;
    USE SIGNAL ;
    ANTENNAGATEAREA 0.396000 ;
    PORT
      LAYER Metal3 ;
        RECT 0.000 352.800 0.560 353.360 ;
    END
  END tl_i[101]
  PIN tl_i[102]
    DIRECTION INPUT ;
    USE SIGNAL ;
    ANTENNAGATEAREA 0.396000 ;
    PORT
      LAYER Metal3 ;
        RECT 0.000 353.920 0.560 354.480 ;
    END
  END tl_i[102]
  PIN tl_i[103]
    DIRECTION INPUT ;
    USE SIGNAL ;
    ANTENNAGATEAREA 0.396000 ;
    PORT
      LAYER Metal3 ;
        RECT 0.000 355.040 0.560 355.600 ;
    END
  END tl_i[103]
  PIN tl_i[104]
    DIRECTION INPUT ;
    USE SIGNAL ;
    ANTENNAGATEAREA 0.396000 ;
    PORT
      LAYER Metal3 ;
        RECT 0.000 356.160 0.560 356.720 ;
    END
  END tl_i[104]
  PIN tl_i[105]
    DIRECTION INPUT ;
    USE SIGNAL ;
    ANTENNAGATEAREA 0.396000 ;
    PORT
      LAYER Metal3 ;
        RECT 0.000 357.280 0.560 357.840 ;
    END
  END tl_i[105]
  PIN tl_i[106]
    DIRECTION INPUT ;
    USE SIGNAL ;
    ANTENNAGATEAREA 0.396000 ;
    PORT
      LAYER Metal3 ;
        RECT 0.000 358.400 0.560 358.960 ;
    END
  END tl_i[106]
  PIN tl_i[107]
    DIRECTION INPUT ;
    USE SIGNAL ;
    PORT
      LAYER Metal3 ;
        RECT 0.000 359.520 0.560 360.080 ;
    END
  END tl_i[107]
  PIN tl_i[108]
    DIRECTION INPUT ;
    USE SIGNAL ;
    PORT
      LAYER Metal3 ;
        RECT 0.000 360.640 0.560 361.200 ;
    END
  END tl_i[108]
  PIN tl_i[109]
    DIRECTION INPUT ;
    USE SIGNAL ;
    PORT
      LAYER Metal3 ;
        RECT 0.000 361.760 0.560 362.320 ;
    END
  END tl_i[109]
  PIN tl_i[10]
    DIRECTION INPUT ;
    USE SIGNAL ;
    ANTENNAGATEAREA 0.396000 ;
    PORT
      LAYER Metal3 ;
        RECT 0.000 250.880 0.560 251.440 ;
    END
  END tl_i[10]
  PIN tl_i[110]
    DIRECTION INPUT ;
    USE SIGNAL ;
    ANTENNAGATEAREA 0.396000 ;
    PORT
      LAYER Metal3 ;
        RECT 0.000 362.880 0.560 363.440 ;
    END
  END tl_i[110]
  PIN tl_i[111]
    DIRECTION INPUT ;
    USE SIGNAL ;
    ANTENNAGATEAREA 0.396000 ;
    PORT
      LAYER Metal3 ;
        RECT 0.000 364.000 0.560 364.560 ;
    END
  END tl_i[111]
  PIN tl_i[112]
    DIRECTION INPUT ;
    USE SIGNAL ;
    ANTENNAGATEAREA 0.396000 ;
    PORT
      LAYER Metal3 ;
        RECT 0.000 365.120 0.560 365.680 ;
    END
  END tl_i[112]
  PIN tl_i[113]
    DIRECTION INPUT ;
    USE SIGNAL ;
    ANTENNAGATEAREA 0.396000 ;
    PORT
      LAYER Metal3 ;
        RECT 0.000 366.240 0.560 366.800 ;
    END
  END tl_i[113]
  PIN tl_i[11]
    DIRECTION INPUT ;
    USE SIGNAL ;
    ANTENNAGATEAREA 0.396000 ;
    PORT
      LAYER Metal3 ;
        RECT 0.000 252.000 0.560 252.560 ;
    END
  END tl_i[11]
  PIN tl_i[12]
    DIRECTION INPUT ;
    USE SIGNAL ;
    ANTENNAGATEAREA 0.396000 ;
    PORT
      LAYER Metal3 ;
        RECT 0.000 253.120 0.560 253.680 ;
    END
  END tl_i[12]
  PIN tl_i[13]
    DIRECTION INPUT ;
    USE SIGNAL ;
    ANTENNAGATEAREA 0.396000 ;
    PORT
      LAYER Metal3 ;
        RECT 0.000 254.240 0.560 254.800 ;
    END
  END tl_i[13]
  PIN tl_i[14]
    DIRECTION INPUT ;
    USE SIGNAL ;
    ANTENNAGATEAREA 0.396000 ;
    PORT
      LAYER Metal3 ;
        RECT 0.000 255.360 0.560 255.920 ;
    END
  END tl_i[14]
  PIN tl_i[15]
    DIRECTION INPUT ;
    USE SIGNAL ;
    ANTENNAGATEAREA 0.396000 ;
    PORT
      LAYER Metal3 ;
        RECT 0.000 256.480 0.560 257.040 ;
    END
  END tl_i[15]
  PIN tl_i[16]
    DIRECTION INPUT ;
    USE SIGNAL ;
    ANTENNAGATEAREA 0.396000 ;
    PORT
      LAYER Metal3 ;
        RECT 0.000 257.600 0.560 258.160 ;
    END
  END tl_i[16]
  PIN tl_i[17]
    DIRECTION INPUT ;
    USE SIGNAL ;
    ANTENNAGATEAREA 0.396000 ;
    PORT
      LAYER Metal3 ;
        RECT 0.000 258.720 0.560 259.280 ;
    END
  END tl_i[17]
  PIN tl_i[18]
    DIRECTION INPUT ;
    USE SIGNAL ;
    ANTENNAGATEAREA 0.396000 ;
    PORT
      LAYER Metal3 ;
        RECT 0.000 259.840 0.560 260.400 ;
    END
  END tl_i[18]
  PIN tl_i[19]
    DIRECTION INPUT ;
    USE SIGNAL ;
    PORT
      LAYER Metal3 ;
        RECT 0.000 260.960 0.560 261.520 ;
    END
  END tl_i[19]
  PIN tl_i[1]
    DIRECTION INPUT ;
    USE SIGNAL ;
    ANTENNAGATEAREA 0.396000 ;
    PORT
      LAYER Metal3 ;
        RECT 0.000 240.800 0.560 241.360 ;
    END
  END tl_i[1]
  PIN tl_i[20]
    DIRECTION INPUT ;
    USE SIGNAL ;
    PORT
      LAYER Metal3 ;
        RECT 0.000 262.080 0.560 262.640 ;
    END
  END tl_i[20]
  PIN tl_i[21]
    DIRECTION INPUT ;
    USE SIGNAL ;
    PORT
      LAYER Metal3 ;
        RECT 0.000 263.200 0.560 263.760 ;
    END
  END tl_i[21]
  PIN tl_i[22]
    DIRECTION INPUT ;
    USE SIGNAL ;
    PORT
      LAYER Metal3 ;
        RECT 0.000 264.320 0.560 264.880 ;
    END
  END tl_i[22]
  PIN tl_i[23]
    DIRECTION INPUT ;
    USE SIGNAL ;
    PORT
      LAYER Metal3 ;
        RECT 0.000 265.440 0.560 266.000 ;
    END
  END tl_i[23]
  PIN tl_i[24]
    DIRECTION INPUT ;
    USE SIGNAL ;
    PORT
      LAYER Metal3 ;
        RECT 0.000 266.560 0.560 267.120 ;
    END
  END tl_i[24]
  PIN tl_i[25]
    DIRECTION INPUT ;
    USE SIGNAL ;
    PORT
      LAYER Metal3 ;
        RECT 0.000 267.680 0.560 268.240 ;
    END
  END tl_i[25]
  PIN tl_i[26]
    DIRECTION INPUT ;
    USE SIGNAL ;
    PORT
      LAYER Metal3 ;
        RECT 0.000 268.800 0.560 269.360 ;
    END
  END tl_i[26]
  PIN tl_i[27]
    DIRECTION INPUT ;
    USE SIGNAL ;
    PORT
      LAYER Metal3 ;
        RECT 0.000 269.920 0.560 270.480 ;
    END
  END tl_i[27]
  PIN tl_i[28]
    DIRECTION INPUT ;
    USE SIGNAL ;
    PORT
      LAYER Metal3 ;
        RECT 0.000 271.040 0.560 271.600 ;
    END
  END tl_i[28]
  PIN tl_i[29]
    DIRECTION INPUT ;
    USE SIGNAL ;
    ANTENNAGATEAREA 0.396000 ;
    PORT
      LAYER Metal3 ;
        RECT 0.000 272.160 0.560 272.720 ;
    END
  END tl_i[29]
  PIN tl_i[2]
    DIRECTION INPUT ;
    USE SIGNAL ;
    ANTENNAGATEAREA 0.396000 ;
    PORT
      LAYER Metal3 ;
        RECT 0.000 241.920 0.560 242.480 ;
    END
  END tl_i[2]
  PIN tl_i[30]
    DIRECTION INPUT ;
    USE SIGNAL ;
    ANTENNAGATEAREA 0.396000 ;
    PORT
      LAYER Metal3 ;
        RECT 0.000 273.280 0.560 273.840 ;
    END
  END tl_i[30]
  PIN tl_i[31]
    DIRECTION INPUT ;
    USE SIGNAL ;
    ANTENNAGATEAREA 0.396000 ;
    PORT
      LAYER Metal3 ;
        RECT 0.000 274.400 0.560 274.960 ;
    END
  END tl_i[31]
  PIN tl_i[32]
    DIRECTION INPUT ;
    USE SIGNAL ;
    ANTENNAGATEAREA 0.396000 ;
    PORT
      LAYER Metal3 ;
        RECT 0.000 275.520 0.560 276.080 ;
    END
  END tl_i[32]
  PIN tl_i[33]
    DIRECTION INPUT ;
    USE SIGNAL ;
    ANTENNAGATEAREA 0.396000 ;
    PORT
      LAYER Metal3 ;
        RECT 0.000 276.640 0.560 277.200 ;
    END
  END tl_i[33]
  PIN tl_i[34]
    DIRECTION INPUT ;
    USE SIGNAL ;
    ANTENNAGATEAREA 0.396000 ;
    PORT
      LAYER Metal3 ;
        RECT 0.000 277.760 0.560 278.320 ;
    END
  END tl_i[34]
  PIN tl_i[35]
    DIRECTION INPUT ;
    USE SIGNAL ;
    ANTENNAGATEAREA 0.396000 ;
    PORT
      LAYER Metal3 ;
        RECT 0.000 278.880 0.560 279.440 ;
    END
  END tl_i[35]
  PIN tl_i[36]
    DIRECTION INPUT ;
    USE SIGNAL ;
    ANTENNAGATEAREA 0.396000 ;
    PORT
      LAYER Metal3 ;
        RECT 0.000 280.000 0.560 280.560 ;
    END
  END tl_i[36]
  PIN tl_i[37]
    DIRECTION INPUT ;
    USE SIGNAL ;
    ANTENNAGATEAREA 0.396000 ;
    PORT
      LAYER Metal3 ;
        RECT 0.000 281.120 0.560 281.680 ;
    END
  END tl_i[37]
  PIN tl_i[38]
    DIRECTION INPUT ;
    USE SIGNAL ;
    ANTENNAGATEAREA 0.396000 ;
    PORT
      LAYER Metal3 ;
        RECT 0.000 282.240 0.560 282.800 ;
    END
  END tl_i[38]
  PIN tl_i[39]
    DIRECTION INPUT ;
    USE SIGNAL ;
    ANTENNAGATEAREA 0.396000 ;
    PORT
      LAYER Metal3 ;
        RECT 0.000 283.360 0.560 283.920 ;
    END
  END tl_i[39]
  PIN tl_i[3]
    DIRECTION INPUT ;
    USE SIGNAL ;
    ANTENNAGATEAREA 0.396000 ;
    PORT
      LAYER Metal3 ;
        RECT 0.000 243.040 0.560 243.600 ;
    END
  END tl_i[3]
  PIN tl_i[40]
    DIRECTION INPUT ;
    USE SIGNAL ;
    ANTENNAGATEAREA 0.396000 ;
    PORT
      LAYER Metal3 ;
        RECT 0.000 284.480 0.560 285.040 ;
    END
  END tl_i[40]
  PIN tl_i[41]
    DIRECTION INPUT ;
    USE SIGNAL ;
    ANTENNAGATEAREA 0.396000 ;
    PORT
      LAYER Metal3 ;
        RECT 0.000 285.600 0.560 286.160 ;
    END
  END tl_i[41]
  PIN tl_i[42]
    DIRECTION INPUT ;
    USE SIGNAL ;
    ANTENNAGATEAREA 0.396000 ;
    PORT
      LAYER Metal3 ;
        RECT 0.000 286.720 0.560 287.280 ;
    END
  END tl_i[42]
  PIN tl_i[43]
    DIRECTION INPUT ;
    USE SIGNAL ;
    ANTENNAGATEAREA 0.396000 ;
    PORT
      LAYER Metal3 ;
        RECT 0.000 287.840 0.560 288.400 ;
    END
  END tl_i[43]
  PIN tl_i[44]
    DIRECTION INPUT ;
    USE SIGNAL ;
    ANTENNAGATEAREA 0.396000 ;
    PORT
      LAYER Metal3 ;
        RECT 0.000 288.960 0.560 289.520 ;
    END
  END tl_i[44]
  PIN tl_i[45]
    DIRECTION INPUT ;
    USE SIGNAL ;
    ANTENNAGATEAREA 0.396000 ;
    PORT
      LAYER Metal3 ;
        RECT 0.000 290.080 0.560 290.640 ;
    END
  END tl_i[45]
  PIN tl_i[46]
    DIRECTION INPUT ;
    USE SIGNAL ;
    ANTENNAGATEAREA 0.396000 ;
    PORT
      LAYER Metal3 ;
        RECT 0.000 291.200 0.560 291.760 ;
    END
  END tl_i[46]
  PIN tl_i[47]
    DIRECTION INPUT ;
    USE SIGNAL ;
    ANTENNAGATEAREA 0.396000 ;
    PORT
      LAYER Metal3 ;
        RECT 0.000 292.320 0.560 292.880 ;
    END
  END tl_i[47]
  PIN tl_i[48]
    DIRECTION INPUT ;
    USE SIGNAL ;
    ANTENNAGATEAREA 0.396000 ;
    PORT
      LAYER Metal3 ;
        RECT 0.000 293.440 0.560 294.000 ;
    END
  END tl_i[48]
  PIN tl_i[49]
    DIRECTION INPUT ;
    USE SIGNAL ;
    ANTENNAGATEAREA 0.396000 ;
    PORT
      LAYER Metal3 ;
        RECT 0.000 294.560 0.560 295.120 ;
    END
  END tl_i[49]
  PIN tl_i[4]
    DIRECTION INPUT ;
    USE SIGNAL ;
    ANTENNAGATEAREA 0.396000 ;
    PORT
      LAYER Metal3 ;
        RECT 0.000 244.160 0.560 244.720 ;
    END
  END tl_i[4]
  PIN tl_i[50]
    DIRECTION INPUT ;
    USE SIGNAL ;
    ANTENNAGATEAREA 0.396000 ;
    PORT
      LAYER Metal3 ;
        RECT 0.000 295.680 0.560 296.240 ;
    END
  END tl_i[50]
  PIN tl_i[51]
    DIRECTION INPUT ;
    USE SIGNAL ;
    ANTENNAGATEAREA 0.396000 ;
    PORT
      LAYER Metal3 ;
        RECT 0.000 296.800 0.560 297.360 ;
    END
  END tl_i[51]
  PIN tl_i[52]
    DIRECTION INPUT ;
    USE SIGNAL ;
    ANTENNAGATEAREA 0.396000 ;
    PORT
      LAYER Metal3 ;
        RECT 0.000 297.920 0.560 298.480 ;
    END
  END tl_i[52]
  PIN tl_i[53]
    DIRECTION INPUT ;
    USE SIGNAL ;
    ANTENNAGATEAREA 0.396000 ;
    PORT
      LAYER Metal3 ;
        RECT 0.000 299.040 0.560 299.600 ;
    END
  END tl_i[53]
  PIN tl_i[54]
    DIRECTION INPUT ;
    USE SIGNAL ;
    ANTENNAGATEAREA 0.396000 ;
    PORT
      LAYER Metal3 ;
        RECT 0.000 300.160 0.560 300.720 ;
    END
  END tl_i[54]
  PIN tl_i[55]
    DIRECTION INPUT ;
    USE SIGNAL ;
    ANTENNAGATEAREA 0.396000 ;
    PORT
      LAYER Metal3 ;
        RECT 0.000 301.280 0.560 301.840 ;
    END
  END tl_i[55]
  PIN tl_i[56]
    DIRECTION INPUT ;
    USE SIGNAL ;
    ANTENNAGATEAREA 0.396000 ;
    PORT
      LAYER Metal3 ;
        RECT 0.000 302.400 0.560 302.960 ;
    END
  END tl_i[56]
  PIN tl_i[57]
    DIRECTION INPUT ;
    USE SIGNAL ;
    ANTENNAGATEAREA 0.396000 ;
    PORT
      LAYER Metal3 ;
        RECT 0.000 303.520 0.560 304.080 ;
    END
  END tl_i[57]
  PIN tl_i[58]
    DIRECTION INPUT ;
    USE SIGNAL ;
    ANTENNAGATEAREA 0.396000 ;
    PORT
      LAYER Metal3 ;
        RECT 0.000 304.640 0.560 305.200 ;
    END
  END tl_i[58]
  PIN tl_i[59]
    DIRECTION INPUT ;
    USE SIGNAL ;
    ANTENNAGATEAREA 0.396000 ;
    PORT
      LAYER Metal3 ;
        RECT 0.000 305.760 0.560 306.320 ;
    END
  END tl_i[59]
  PIN tl_i[5]
    DIRECTION INPUT ;
    USE SIGNAL ;
    ANTENNAGATEAREA 0.396000 ;
    PORT
      LAYER Metal3 ;
        RECT 0.000 245.280 0.560 245.840 ;
    END
  END tl_i[5]
  PIN tl_i[60]
    DIRECTION INPUT ;
    USE SIGNAL ;
    ANTENNAGATEAREA 0.396000 ;
    PORT
      LAYER Metal3 ;
        RECT 0.000 306.880 0.560 307.440 ;
    END
  END tl_i[60]
  PIN tl_i[61]
    DIRECTION INPUT ;
    USE SIGNAL ;
    ANTENNAGATEAREA 0.396000 ;
    PORT
      LAYER Metal3 ;
        RECT 0.000 308.000 0.560 308.560 ;
    END
  END tl_i[61]
  PIN tl_i[62]
    DIRECTION INPUT ;
    USE SIGNAL ;
    ANTENNAGATEAREA 0.396000 ;
    PORT
      LAYER Metal3 ;
        RECT 0.000 309.120 0.560 309.680 ;
    END
  END tl_i[62]
  PIN tl_i[63]
    DIRECTION INPUT ;
    USE SIGNAL ;
    ANTENNAGATEAREA 0.396000 ;
    PORT
      LAYER Metal3 ;
        RECT 0.000 310.240 0.560 310.800 ;
    END
  END tl_i[63]
  PIN tl_i[64]
    DIRECTION INPUT ;
    USE SIGNAL ;
    ANTENNAGATEAREA 0.396000 ;
    PORT
      LAYER Metal3 ;
        RECT 0.000 311.360 0.560 311.920 ;
    END
  END tl_i[64]
  PIN tl_i[65]
    DIRECTION INPUT ;
    USE SIGNAL ;
    ANTENNAGATEAREA 0.396000 ;
    PORT
      LAYER Metal3 ;
        RECT 0.000 312.480 0.560 313.040 ;
    END
  END tl_i[65]
  PIN tl_i[66]
    DIRECTION INPUT ;
    USE SIGNAL ;
    ANTENNAGATEAREA 0.396000 ;
    PORT
      LAYER Metal3 ;
        RECT 0.000 313.600 0.560 314.160 ;
    END
  END tl_i[66]
  PIN tl_i[67]
    DIRECTION INPUT ;
    USE SIGNAL ;
    ANTENNAGATEAREA 0.396000 ;
    PORT
      LAYER Metal3 ;
        RECT 0.000 314.720 0.560 315.280 ;
    END
  END tl_i[67]
  PIN tl_i[68]
    DIRECTION INPUT ;
    USE SIGNAL ;
    ANTENNAGATEAREA 0.396000 ;
    PORT
      LAYER Metal3 ;
        RECT 0.000 315.840 0.560 316.400 ;
    END
  END tl_i[68]
  PIN tl_i[69]
    DIRECTION INPUT ;
    USE SIGNAL ;
    ANTENNAGATEAREA 0.396000 ;
    PORT
      LAYER Metal3 ;
        RECT 0.000 316.960 0.560 317.520 ;
    END
  END tl_i[69]
  PIN tl_i[6]
    DIRECTION INPUT ;
    USE SIGNAL ;
    ANTENNAGATEAREA 0.396000 ;
    PORT
      LAYER Metal3 ;
        RECT 0.000 246.400 0.560 246.960 ;
    END
  END tl_i[6]
  PIN tl_i[70]
    DIRECTION INPUT ;
    USE SIGNAL ;
    ANTENNAGATEAREA 0.396000 ;
    PORT
      LAYER Metal3 ;
        RECT 0.000 318.080 0.560 318.640 ;
    END
  END tl_i[70]
  PIN tl_i[71]
    DIRECTION INPUT ;
    USE SIGNAL ;
    ANTENNAGATEAREA 0.396000 ;
    PORT
      LAYER Metal3 ;
        RECT 0.000 319.200 0.560 319.760 ;
    END
  END tl_i[71]
  PIN tl_i[72]
    DIRECTION INPUT ;
    USE SIGNAL ;
    ANTENNAGATEAREA 0.396000 ;
    PORT
      LAYER Metal3 ;
        RECT 0.000 320.320 0.560 320.880 ;
    END
  END tl_i[72]
  PIN tl_i[73]
    DIRECTION INPUT ;
    USE SIGNAL ;
    ANTENNAGATEAREA 0.396000 ;
    PORT
      LAYER Metal3 ;
        RECT 0.000 321.440 0.560 322.000 ;
    END
  END tl_i[73]
  PIN tl_i[74]
    DIRECTION INPUT ;
    USE SIGNAL ;
    ANTENNAGATEAREA 0.396000 ;
    PORT
      LAYER Metal3 ;
        RECT 0.000 322.560 0.560 323.120 ;
    END
  END tl_i[74]
  PIN tl_i[75]
    DIRECTION INPUT ;
    USE SIGNAL ;
    ANTENNAGATEAREA 0.396000 ;
    PORT
      LAYER Metal3 ;
        RECT 0.000 323.680 0.560 324.240 ;
    END
  END tl_i[75]
  PIN tl_i[76]
    DIRECTION INPUT ;
    USE SIGNAL ;
    ANTENNAGATEAREA 0.396000 ;
    PORT
      LAYER Metal3 ;
        RECT 0.000 324.800 0.560 325.360 ;
    END
  END tl_i[76]
  PIN tl_i[77]
    DIRECTION INPUT ;
    USE SIGNAL ;
    ANTENNAGATEAREA 0.396000 ;
    PORT
      LAYER Metal3 ;
        RECT 0.000 325.920 0.560 326.480 ;
    END
  END tl_i[77]
  PIN tl_i[78]
    DIRECTION INPUT ;
    USE SIGNAL ;
    ANTENNAGATEAREA 0.396000 ;
    PORT
      LAYER Metal3 ;
        RECT 0.000 327.040 0.560 327.600 ;
    END
  END tl_i[78]
  PIN tl_i[79]
    DIRECTION INPUT ;
    USE SIGNAL ;
    ANTENNAGATEAREA 0.396000 ;
    PORT
      LAYER Metal3 ;
        RECT 0.000 328.160 0.560 328.720 ;
    END
  END tl_i[79]
  PIN tl_i[7]
    DIRECTION INPUT ;
    USE SIGNAL ;
    ANTENNAGATEAREA 0.396000 ;
    PORT
      LAYER Metal3 ;
        RECT 0.000 247.520 0.560 248.080 ;
    END
  END tl_i[7]
  PIN tl_i[80]
    DIRECTION INPUT ;
    USE SIGNAL ;
    ANTENNAGATEAREA 0.396000 ;
    PORT
      LAYER Metal3 ;
        RECT 0.000 329.280 0.560 329.840 ;
    END
  END tl_i[80]
  PIN tl_i[81]
    DIRECTION INPUT ;
    USE SIGNAL ;
    ANTENNAGATEAREA 0.396000 ;
    PORT
      LAYER Metal3 ;
        RECT 0.000 330.400 0.560 330.960 ;
    END
  END tl_i[81]
  PIN tl_i[82]
    DIRECTION INPUT ;
    USE SIGNAL ;
    ANTENNAGATEAREA 0.396000 ;
    PORT
      LAYER Metal3 ;
        RECT 0.000 331.520 0.560 332.080 ;
    END
  END tl_i[82]
  PIN tl_i[83]
    DIRECTION INPUT ;
    USE SIGNAL ;
    ANTENNAGATEAREA 0.396000 ;
    PORT
      LAYER Metal3 ;
        RECT 0.000 332.640 0.560 333.200 ;
    END
  END tl_i[83]
  PIN tl_i[84]
    DIRECTION INPUT ;
    USE SIGNAL ;
    ANTENNAGATEAREA 0.396000 ;
    PORT
      LAYER Metal3 ;
        RECT 0.000 333.760 0.560 334.320 ;
    END
  END tl_i[84]
  PIN tl_i[85]
    DIRECTION INPUT ;
    USE SIGNAL ;
    ANTENNAGATEAREA 0.396000 ;
    PORT
      LAYER Metal3 ;
        RECT 0.000 334.880 0.560 335.440 ;
    END
  END tl_i[85]
  PIN tl_i[86]
    DIRECTION INPUT ;
    USE SIGNAL ;
    ANTENNAGATEAREA 0.396000 ;
    PORT
      LAYER Metal3 ;
        RECT 0.000 336.000 0.560 336.560 ;
    END
  END tl_i[86]
  PIN tl_i[87]
    DIRECTION INPUT ;
    USE SIGNAL ;
    ANTENNAGATEAREA 0.396000 ;
    PORT
      LAYER Metal3 ;
        RECT 0.000 337.120 0.560 337.680 ;
    END
  END tl_i[87]
  PIN tl_i[88]
    DIRECTION INPUT ;
    USE SIGNAL ;
    ANTENNAGATEAREA 0.396000 ;
    PORT
      LAYER Metal3 ;
        RECT 0.000 338.240 0.560 338.800 ;
    END
  END tl_i[88]
  PIN tl_i[89]
    DIRECTION INPUT ;
    USE SIGNAL ;
    ANTENNAGATEAREA 0.396000 ;
    PORT
      LAYER Metal3 ;
        RECT 0.000 339.360 0.560 339.920 ;
    END
  END tl_i[89]
  PIN tl_i[8]
    DIRECTION INPUT ;
    USE SIGNAL ;
    ANTENNAGATEAREA 0.396000 ;
    PORT
      LAYER Metal3 ;
        RECT 0.000 248.640 0.560 249.200 ;
    END
  END tl_i[8]
  PIN tl_i[90]
    DIRECTION INPUT ;
    USE SIGNAL ;
    ANTENNAGATEAREA 0.396000 ;
    PORT
      LAYER Metal3 ;
        RECT 0.000 340.480 0.560 341.040 ;
    END
  END tl_i[90]
  PIN tl_i[91]
    DIRECTION INPUT ;
    USE SIGNAL ;
    ANTENNAGATEAREA 0.396000 ;
    PORT
      LAYER Metal3 ;
        RECT 0.000 341.600 0.560 342.160 ;
    END
  END tl_i[91]
  PIN tl_i[92]
    DIRECTION INPUT ;
    USE SIGNAL ;
    ANTENNAGATEAREA 0.396000 ;
    PORT
      LAYER Metal3 ;
        RECT 0.000 342.720 0.560 343.280 ;
    END
  END tl_i[92]
  PIN tl_i[93]
    DIRECTION INPUT ;
    USE SIGNAL ;
    ANTENNAGATEAREA 0.396000 ;
    PORT
      LAYER Metal3 ;
        RECT 0.000 343.840 0.560 344.400 ;
    END
  END tl_i[93]
  PIN tl_i[94]
    DIRECTION INPUT ;
    USE SIGNAL ;
    ANTENNAGATEAREA 0.396000 ;
    PORT
      LAYER Metal3 ;
        RECT 0.000 344.960 0.560 345.520 ;
    END
  END tl_i[94]
  PIN tl_i[95]
    DIRECTION INPUT ;
    USE SIGNAL ;
    ANTENNAGATEAREA 0.396000 ;
    PORT
      LAYER Metal3 ;
        RECT 0.000 346.080 0.560 346.640 ;
    END
  END tl_i[95]
  PIN tl_i[96]
    DIRECTION INPUT ;
    USE SIGNAL ;
    ANTENNAGATEAREA 0.396000 ;
    PORT
      LAYER Metal3 ;
        RECT 0.000 347.200 0.560 347.760 ;
    END
  END tl_i[96]
  PIN tl_i[97]
    DIRECTION INPUT ;
    USE SIGNAL ;
    ANTENNAGATEAREA 0.396000 ;
    PORT
      LAYER Metal3 ;
        RECT 0.000 348.320 0.560 348.880 ;
    END
  END tl_i[97]
  PIN tl_i[98]
    DIRECTION INPUT ;
    USE SIGNAL ;
    ANTENNAGATEAREA 0.396000 ;
    PORT
      LAYER Metal3 ;
        RECT 0.000 349.440 0.560 350.000 ;
    END
  END tl_i[98]
  PIN tl_i[99]
    DIRECTION INPUT ;
    USE SIGNAL ;
    ANTENNAGATEAREA 0.396000 ;
    PORT
      LAYER Metal3 ;
        RECT 0.000 350.560 0.560 351.120 ;
    END
  END tl_i[99]
  PIN tl_i[9]
    DIRECTION INPUT ;
    USE SIGNAL ;
    ANTENNAGATEAREA 0.396000 ;
    PORT
      LAYER Metal3 ;
        RECT 0.000 249.760 0.560 250.320 ;
    END
  END tl_i[9]
  PIN tl_o[0]
    DIRECTION OUTPUT ;
    USE SIGNAL ;
    ANTENNADIFFAREA 0.897600 ;
    PORT
      LAYER Metal3 ;
        RECT 0.000 367.360 0.560 367.920 ;
    END
  END tl_o[0]
  PIN tl_o[10]
    DIRECTION OUTPUT ;
    USE SIGNAL ;
    ANTENNADIFFAREA 0.897600 ;
    PORT
      LAYER Metal3 ;
        RECT 0.000 378.560 0.560 379.120 ;
    END
  END tl_o[10]
  PIN tl_o[11]
    DIRECTION OUTPUT ;
    USE SIGNAL ;
    ANTENNADIFFAREA 0.897600 ;
    PORT
      LAYER Metal3 ;
        RECT 0.000 379.680 0.560 380.240 ;
    END
  END tl_o[11]
  PIN tl_o[12]
    DIRECTION OUTPUT ;
    USE SIGNAL ;
    ANTENNADIFFAREA 0.897600 ;
    PORT
      LAYER Metal3 ;
        RECT 0.000 380.800 0.560 381.360 ;
    END
  END tl_o[12]
  PIN tl_o[13]
    DIRECTION OUTPUT ;
    USE SIGNAL ;
    ANTENNADIFFAREA 0.897600 ;
    PORT
      LAYER Metal3 ;
        RECT 0.000 381.920 0.560 382.480 ;
    END
  END tl_o[13]
  PIN tl_o[14]
    DIRECTION OUTPUT ;
    USE SIGNAL ;
    ANTENNADIFFAREA 0.897600 ;
    PORT
      LAYER Metal3 ;
        RECT 0.000 383.040 0.560 383.600 ;
    END
  END tl_o[14]
  PIN tl_o[15]
    DIRECTION OUTPUT ;
    USE SIGNAL ;
    ANTENNADIFFAREA 0.360800 ;
    PORT
      LAYER Metal3 ;
        RECT 0.000 384.160 0.560 384.720 ;
    END
  END tl_o[15]
  PIN tl_o[16]
    DIRECTION OUTPUT ;
    USE SIGNAL ;
    ANTENNADIFFAREA 0.897600 ;
    PORT
      LAYER Metal3 ;
        RECT 0.000 385.280 0.560 385.840 ;
    END
  END tl_o[16]
  PIN tl_o[17]
    DIRECTION OUTPUT ;
    USE SIGNAL ;
    ANTENNADIFFAREA 0.897600 ;
    PORT
      LAYER Metal3 ;
        RECT 0.000 386.400 0.560 386.960 ;
    END
  END tl_o[17]
  PIN tl_o[18]
    DIRECTION OUTPUT ;
    USE SIGNAL ;
    ANTENNADIFFAREA 0.897600 ;
    PORT
      LAYER Metal3 ;
        RECT 0.000 387.520 0.560 388.080 ;
    END
  END tl_o[18]
  PIN tl_o[19]
    DIRECTION OUTPUT ;
    USE SIGNAL ;
    ANTENNADIFFAREA 0.897600 ;
    PORT
      LAYER Metal3 ;
        RECT 0.000 388.640 0.560 389.200 ;
    END
  END tl_o[19]
  PIN tl_o[1]
    DIRECTION OUTPUT ;
    USE SIGNAL ;
    ANTENNADIFFAREA 0.897600 ;
    PORT
      LAYER Metal3 ;
        RECT 0.000 368.480 0.560 369.040 ;
    END
  END tl_o[1]
  PIN tl_o[20]
    DIRECTION OUTPUT ;
    USE SIGNAL ;
    ANTENNADIFFAREA 0.897600 ;
    PORT
      LAYER Metal3 ;
        RECT 0.000 389.760 0.560 390.320 ;
    END
  END tl_o[20]
  PIN tl_o[21]
    DIRECTION OUTPUT ;
    USE SIGNAL ;
    ANTENNADIFFAREA 0.897600 ;
    PORT
      LAYER Metal3 ;
        RECT 0.000 390.880 0.560 391.440 ;
    END
  END tl_o[21]
  PIN tl_o[22]
    DIRECTION OUTPUT ;
    USE SIGNAL ;
    ANTENNADIFFAREA 0.897600 ;
    PORT
      LAYER Metal3 ;
        RECT 0.000 392.000 0.560 392.560 ;
    END
  END tl_o[22]
  PIN tl_o[23]
    DIRECTION OUTPUT ;
    USE SIGNAL ;
    ANTENNADIFFAREA 0.897600 ;
    PORT
      LAYER Metal3 ;
        RECT 0.000 393.120 0.560 393.680 ;
    END
  END tl_o[23]
  PIN tl_o[24]
    DIRECTION OUTPUT ;
    USE SIGNAL ;
    ANTENNADIFFAREA 0.897600 ;
    PORT
      LAYER Metal3 ;
        RECT 0.000 394.240 0.560 394.800 ;
    END
  END tl_o[24]
  PIN tl_o[25]
    DIRECTION OUTPUT ;
    USE SIGNAL ;
    ANTENNADIFFAREA 0.897600 ;
    PORT
      LAYER Metal3 ;
        RECT 0.000 395.360 0.560 395.920 ;
    END
  END tl_o[25]
  PIN tl_o[26]
    DIRECTION OUTPUT ;
    USE SIGNAL ;
    ANTENNADIFFAREA 0.897600 ;
    PORT
      LAYER Metal3 ;
        RECT 0.000 396.480 0.560 397.040 ;
    END
  END tl_o[26]
  PIN tl_o[27]
    DIRECTION OUTPUT ;
    USE SIGNAL ;
    ANTENNADIFFAREA 0.897600 ;
    PORT
      LAYER Metal3 ;
        RECT 0.000 397.600 0.560 398.160 ;
    END
  END tl_o[27]
  PIN tl_o[28]
    DIRECTION OUTPUT ;
    USE SIGNAL ;
    ANTENNADIFFAREA 0.897600 ;
    PORT
      LAYER Metal3 ;
        RECT 0.000 398.720 0.560 399.280 ;
    END
  END tl_o[28]
  PIN tl_o[29]
    DIRECTION OUTPUT ;
    USE SIGNAL ;
    ANTENNADIFFAREA 0.897600 ;
    PORT
      LAYER Metal3 ;
        RECT 0.000 399.840 0.560 400.400 ;
    END
  END tl_o[29]
  PIN tl_o[2]
    DIRECTION OUTPUT ;
    USE SIGNAL ;
    ANTENNADIFFAREA 0.897600 ;
    PORT
      LAYER Metal3 ;
        RECT 0.000 369.600 0.560 370.160 ;
    END
  END tl_o[2]
  PIN tl_o[30]
    DIRECTION OUTPUT ;
    USE SIGNAL ;
    ANTENNADIFFAREA 0.897600 ;
    PORT
      LAYER Metal3 ;
        RECT 0.000 400.960 0.560 401.520 ;
    END
  END tl_o[30]
  PIN tl_o[31]
    DIRECTION OUTPUT ;
    USE SIGNAL ;
    ANTENNADIFFAREA 0.897600 ;
    PORT
      LAYER Metal3 ;
        RECT 0.000 402.080 0.560 402.640 ;
    END
  END tl_o[31]
  PIN tl_o[32]
    DIRECTION OUTPUT ;
    USE SIGNAL ;
    ANTENNADIFFAREA 0.897600 ;
    PORT
      LAYER Metal3 ;
        RECT 0.000 403.200 0.560 403.760 ;
    END
  END tl_o[32]
  PIN tl_o[33]
    DIRECTION OUTPUT ;
    USE SIGNAL ;
    ANTENNADIFFAREA 0.897600 ;
    PORT
      LAYER Metal3 ;
        RECT 0.000 404.320 0.560 404.880 ;
    END
  END tl_o[33]
  PIN tl_o[34]
    DIRECTION OUTPUT ;
    USE SIGNAL ;
    ANTENNADIFFAREA 0.897600 ;
    PORT
      LAYER Metal3 ;
        RECT 0.000 405.440 0.560 406.000 ;
    END
  END tl_o[34]
  PIN tl_o[35]
    DIRECTION OUTPUT ;
    USE SIGNAL ;
    ANTENNADIFFAREA 0.897600 ;
    PORT
      LAYER Metal3 ;
        RECT 0.000 406.560 0.560 407.120 ;
    END
  END tl_o[35]
  PIN tl_o[36]
    DIRECTION OUTPUT ;
    USE SIGNAL ;
    ANTENNADIFFAREA 0.897600 ;
    PORT
      LAYER Metal3 ;
        RECT 0.000 407.680 0.560 408.240 ;
    END
  END tl_o[36]
  PIN tl_o[37]
    DIRECTION OUTPUT ;
    USE SIGNAL ;
    ANTENNADIFFAREA 0.897600 ;
    PORT
      LAYER Metal3 ;
        RECT 0.000 408.800 0.560 409.360 ;
    END
  END tl_o[37]
  PIN tl_o[38]
    DIRECTION OUTPUT ;
    USE SIGNAL ;
    ANTENNADIFFAREA 0.897600 ;
    PORT
      LAYER Metal3 ;
        RECT 0.000 409.920 0.560 410.480 ;
    END
  END tl_o[38]
  PIN tl_o[39]
    DIRECTION OUTPUT ;
    USE SIGNAL ;
    ANTENNADIFFAREA 0.897600 ;
    PORT
      LAYER Metal3 ;
        RECT 0.000 411.040 0.560 411.600 ;
    END
  END tl_o[39]
  PIN tl_o[3]
    DIRECTION OUTPUT ;
    USE SIGNAL ;
    ANTENNADIFFAREA 0.897600 ;
    PORT
      LAYER Metal3 ;
        RECT 0.000 370.720 0.560 371.280 ;
    END
  END tl_o[3]
  PIN tl_o[40]
    DIRECTION OUTPUT ;
    USE SIGNAL ;
    ANTENNADIFFAREA 0.897600 ;
    PORT
      LAYER Metal3 ;
        RECT 0.000 412.160 0.560 412.720 ;
    END
  END tl_o[40]
  PIN tl_o[41]
    DIRECTION OUTPUT ;
    USE SIGNAL ;
    ANTENNADIFFAREA 0.897600 ;
    PORT
      LAYER Metal3 ;
        RECT 0.000 413.280 0.560 413.840 ;
    END
  END tl_o[41]
  PIN tl_o[42]
    DIRECTION OUTPUT ;
    USE SIGNAL ;
    ANTENNADIFFAREA 0.897600 ;
    PORT
      LAYER Metal3 ;
        RECT 0.000 414.400 0.560 414.960 ;
    END
  END tl_o[42]
  PIN tl_o[43]
    DIRECTION OUTPUT ;
    USE SIGNAL ;
    ANTENNADIFFAREA 0.897600 ;
    PORT
      LAYER Metal3 ;
        RECT 0.000 415.520 0.560 416.080 ;
    END
  END tl_o[43]
  PIN tl_o[44]
    DIRECTION OUTPUT ;
    USE SIGNAL ;
    ANTENNADIFFAREA 0.897600 ;
    PORT
      LAYER Metal3 ;
        RECT 0.000 416.640 0.560 417.200 ;
    END
  END tl_o[44]
  PIN tl_o[45]
    DIRECTION OUTPUT ;
    USE SIGNAL ;
    ANTENNADIFFAREA 0.897600 ;
    PORT
      LAYER Metal3 ;
        RECT 0.000 417.760 0.560 418.320 ;
    END
  END tl_o[45]
  PIN tl_o[46]
    DIRECTION OUTPUT ;
    USE SIGNAL ;
    ANTENNADIFFAREA 0.897600 ;
    PORT
      LAYER Metal3 ;
        RECT 0.000 418.880 0.560 419.440 ;
    END
  END tl_o[46]
  PIN tl_o[47]
    DIRECTION OUTPUT ;
    USE SIGNAL ;
    ANTENNADIFFAREA 0.897600 ;
    PORT
      LAYER Metal3 ;
        RECT 0.000 420.000 0.560 420.560 ;
    END
  END tl_o[47]
  PIN tl_o[48]
    DIRECTION OUTPUT ;
    USE SIGNAL ;
    ANTENNADIFFAREA 0.360800 ;
    PORT
      LAYER Metal3 ;
        RECT 0.000 421.120 0.560 421.680 ;
    END
  END tl_o[48]
  PIN tl_o[49]
    DIRECTION OUTPUT ;
    USE SIGNAL ;
    ANTENNADIFFAREA 0.897600 ;
    PORT
      LAYER Metal3 ;
        RECT 0.000 422.240 0.560 422.800 ;
    END
  END tl_o[49]
  PIN tl_o[4]
    DIRECTION OUTPUT ;
    USE SIGNAL ;
    ANTENNADIFFAREA 0.897600 ;
    PORT
      LAYER Metal3 ;
        RECT 0.000 371.840 0.560 372.400 ;
    END
  END tl_o[4]
  PIN tl_o[50]
    DIRECTION OUTPUT ;
    USE SIGNAL ;
    ANTENNADIFFAREA 0.897600 ;
    PORT
      LAYER Metal3 ;
        RECT 0.000 423.360 0.560 423.920 ;
    END
  END tl_o[50]
  PIN tl_o[51]
    DIRECTION OUTPUT ;
    USE SIGNAL ;
    ANTENNADIFFAREA 0.897600 ;
    PORT
      LAYER Metal3 ;
        RECT 0.000 424.480 0.560 425.040 ;
    END
  END tl_o[51]
  PIN tl_o[52]
    DIRECTION OUTPUT ;
    USE SIGNAL ;
    ANTENNADIFFAREA 0.897600 ;
    PORT
      LAYER Metal3 ;
        RECT 0.000 425.600 0.560 426.160 ;
    END
  END tl_o[52]
  PIN tl_o[53]
    DIRECTION OUTPUT ;
    USE SIGNAL ;
    ANTENNADIFFAREA 0.897600 ;
    PORT
      LAYER Metal3 ;
        RECT 0.000 426.720 0.560 427.280 ;
    END
  END tl_o[53]
  PIN tl_o[54]
    DIRECTION OUTPUT ;
    USE SIGNAL ;
    ANTENNADIFFAREA 0.897600 ;
    PORT
      LAYER Metal3 ;
        RECT 0.000 427.840 0.560 428.400 ;
    END
  END tl_o[54]
  PIN tl_o[55]
    DIRECTION OUTPUT ;
    USE SIGNAL ;
    ANTENNADIFFAREA 0.897600 ;
    PORT
      LAYER Metal3 ;
        RECT 0.000 428.960 0.560 429.520 ;
    END
  END tl_o[55]
  PIN tl_o[56]
    DIRECTION OUTPUT ;
    USE SIGNAL ;
    ANTENNADIFFAREA 0.897600 ;
    PORT
      LAYER Metal3 ;
        RECT 0.000 430.080 0.560 430.640 ;
    END
  END tl_o[56]
  PIN tl_o[57]
    DIRECTION OUTPUT ;
    USE SIGNAL ;
    ANTENNADIFFAREA 0.897600 ;
    PORT
      LAYER Metal3 ;
        RECT 0.000 431.200 0.560 431.760 ;
    END
  END tl_o[57]
  PIN tl_o[58]
    DIRECTION OUTPUT ;
    USE SIGNAL ;
    ANTENNADIFFAREA 0.897600 ;
    PORT
      LAYER Metal3 ;
        RECT 0.000 432.320 0.560 432.880 ;
    END
  END tl_o[58]
  PIN tl_o[59]
    DIRECTION OUTPUT ;
    USE SIGNAL ;
    ANTENNADIFFAREA 0.360800 ;
    PORT
      LAYER Metal3 ;
        RECT 0.000 433.440 0.560 434.000 ;
    END
  END tl_o[59]
  PIN tl_o[5]
    DIRECTION OUTPUT ;
    USE SIGNAL ;
    ANTENNADIFFAREA 0.897600 ;
    PORT
      LAYER Metal3 ;
        RECT 0.000 372.960 0.560 373.520 ;
    END
  END tl_o[5]
  PIN tl_o[60]
    DIRECTION OUTPUT ;
    USE SIGNAL ;
    ANTENNADIFFAREA 0.360800 ;
    PORT
      LAYER Metal3 ;
        RECT 0.000 434.560 0.560 435.120 ;
    END
  END tl_o[60]
  PIN tl_o[61]
    DIRECTION OUTPUT ;
    USE SIGNAL ;
    ANTENNADIFFAREA 0.360800 ;
    PORT
      LAYER Metal3 ;
        RECT 0.000 435.680 0.560 436.240 ;
    END
  END tl_o[61]
  PIN tl_o[62]
    DIRECTION OUTPUT ;
    USE SIGNAL ;
    ANTENNADIFFAREA 0.897600 ;
    PORT
      LAYER Metal3 ;
        RECT 0.000 436.800 0.560 437.360 ;
    END
  END tl_o[62]
  PIN tl_o[63]
    DIRECTION OUTPUT ;
    USE SIGNAL ;
    ANTENNADIFFAREA 0.360800 ;
    PORT
      LAYER Metal3 ;
        RECT 0.000 437.920 0.560 438.480 ;
    END
  END tl_o[63]
  PIN tl_o[64]
    DIRECTION OUTPUT ;
    USE SIGNAL ;
    ANTENNADIFFAREA 0.360800 ;
    PORT
      LAYER Metal3 ;
        RECT 0.000 439.040 0.560 439.600 ;
    END
  END tl_o[64]
  PIN tl_o[65]
    DIRECTION OUTPUT ;
    USE SIGNAL ;
    ANTENNADIFFAREA 0.897600 ;
    PORT
      LAYER Metal3 ;
        RECT 0.000 440.160 0.560 440.720 ;
    END
  END tl_o[65]
  PIN tl_o[6]
    DIRECTION OUTPUT ;
    USE SIGNAL ;
    ANTENNADIFFAREA 0.897600 ;
    PORT
      LAYER Metal3 ;
        RECT 0.000 374.080 0.560 374.640 ;
    END
  END tl_o[6]
  PIN tl_o[7]
    DIRECTION OUTPUT ;
    USE SIGNAL ;
    ANTENNADIFFAREA 0.897600 ;
    PORT
      LAYER Metal3 ;
        RECT 0.000 375.200 0.560 375.760 ;
    END
  END tl_o[7]
  PIN tl_o[8]
    DIRECTION OUTPUT ;
    USE SIGNAL ;
    ANTENNADIFFAREA 0.897600 ;
    PORT
      LAYER Metal3 ;
        RECT 0.000 376.320 0.560 376.880 ;
    END
  END tl_o[8]
  PIN tl_o[9]
    DIRECTION OUTPUT ;
    USE SIGNAL ;
    ANTENNADIFFAREA 0.897600 ;
    PORT
      LAYER Metal3 ;
        RECT 0.000 377.440 0.560 378.000 ;
    END
  END tl_o[9]
  OBS
      LAYER Nwell ;
        RECT 6.290 15.250 558.190 482.590 ;
      LAYER Metal1 ;
        RECT 6.720 15.380 557.760 482.460 ;
      LAYER Metal2 ;
        RECT 0.140 6.250 532.980 499.990 ;
      LAYER Metal3 ;
        RECT 0.090 441.020 533.030 499.940 ;
        RECT 0.860 59.060 533.030 441.020 ;
        RECT 0.090 6.300 533.030 59.060 ;
      LAYER Metal4 ;
        RECT 0.700 482.760 513.940 499.990 ;
        RECT 0.700 15.080 21.940 482.760 ;
        RECT 24.140 15.080 25.240 482.760 ;
        RECT 27.440 15.080 175.540 482.760 ;
        RECT 177.740 15.080 178.840 482.760 ;
        RECT 181.040 15.080 329.140 482.760 ;
        RECT 331.340 15.080 332.440 482.760 ;
        RECT 334.640 15.080 482.740 482.760 ;
        RECT 484.940 15.080 486.040 482.760 ;
        RECT 488.240 15.080 513.940 482.760 ;
        RECT 0.700 4.760 513.940 15.080 ;
      LAYER Metal5 ;
        RECT 1.740 343.390 502.820 499.270 ;
        RECT 1.740 340.590 6.120 343.390 ;
        RECT 1.740 340.090 502.820 340.590 ;
        RECT 1.740 337.290 6.120 340.090 ;
        RECT 1.740 190.210 502.820 337.290 ;
        RECT 1.740 187.410 6.120 190.210 ;
        RECT 1.740 186.910 502.820 187.410 ;
        RECT 1.740 184.110 6.120 186.910 ;
        RECT 1.740 37.030 502.820 184.110 ;
        RECT 1.740 34.230 6.120 37.030 ;
        RECT 1.740 33.730 502.820 34.230 ;
        RECT 1.740 30.930 6.120 33.730 ;
        RECT 1.740 4.730 502.820 30.930 ;
  END
END uart
END LIBRARY

